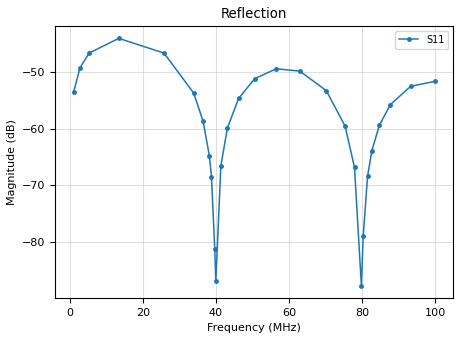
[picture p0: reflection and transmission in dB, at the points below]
# MHz S RI R 50.0
! SimSmith 18.4g
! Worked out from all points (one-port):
!   1000 points, 1 MHz to 100 MHz, reference 50 ohm
!   lowest |S11| = -87.8 dB at 79.78 MHz (marker M1), VSWR 1.00, Z = 50 - j0.00354 ohm
!   |S11| at or under -10 dB: start of sweep to end of sweep
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1  0.0016 0.00136
2.783784  0.00294 0.00186
5.261261  0.00437 0.00169
13.38739  0.0061 -0.00168
25.77478  0.00153 -0.00443
33.9009  -0.0006 -0.00198
36.47748  -0.000539 -0.00103
38.16216  -0.000318 -0.000485
38.75676  -0.00021 -0.000314
39.64865  -2.46e-05 -8.27e-05
39.94595  4.33e-05 -1.26e-05
41.33333  0.000392 0.000263
43.11712  0.000896 0.000485
46.18919  0.00179 0.000502
50.54955  0.00277 -0.000168
56.49549  0.00295 -0.0017
62.93694  0.00169 -0.00277
70.17117  -2.3e-05 -0.00218
75.32432  -0.000406 -0.000977
77.9009  -0.000236 -0.000389
79.78378  2.04e-05 -3.54e-05
80.27928  0.000103 4.25e-05
81.46847  0.000322 0.0002
82.65766  0.000562 0.000311
84.73874  0.00101 0.000389
87.71171  0.00162 0.000242
93.26126  0.00229 -0.000651
100  0.00184 -0.00189
